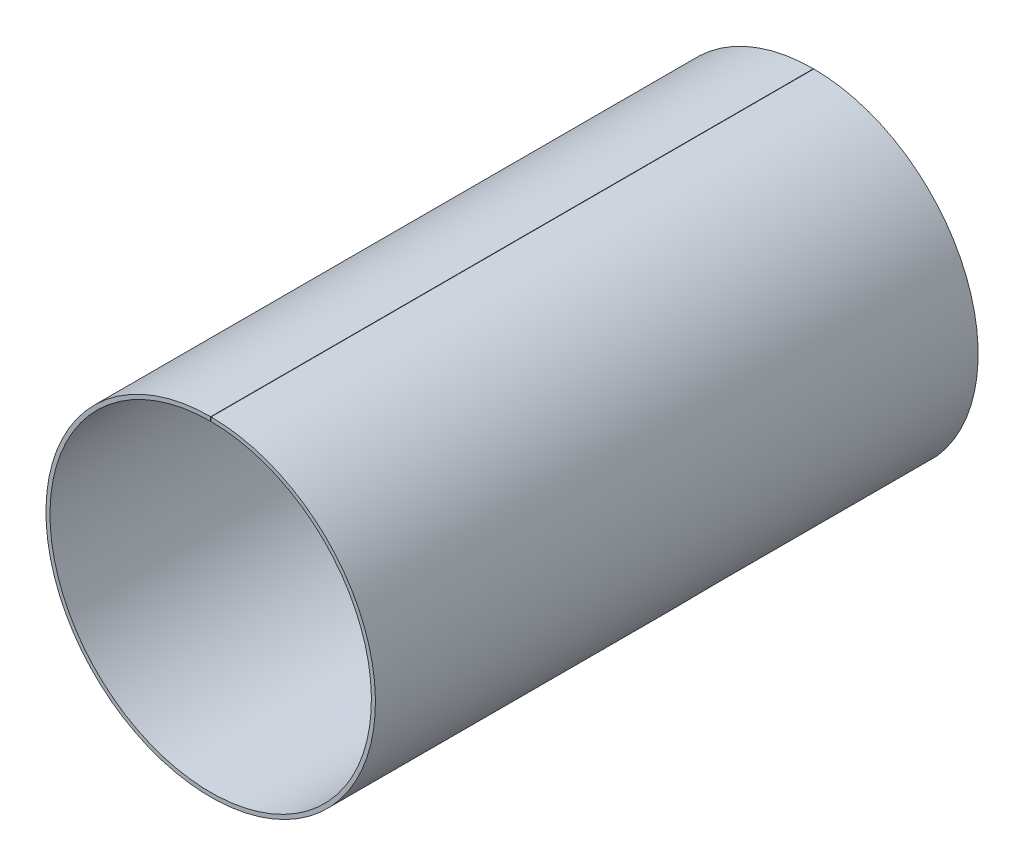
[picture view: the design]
ISO-10303-21;
HEADER;
FILE_DESCRIPTION(('STEP AP214'),'2;1');
FILE_NAME('part.step','',(''),(''),'','','');
FILE_SCHEMA(('AUTOMOTIVE_DESIGN { 1 0 10303 214 1 1 1 1 }'));
ENDSEC;
DATA;
#1=APPLICATION_CONTEXT('core data for automotive mechanical design processes');
#2=APPLICATION_PROTOCOL_DEFINITION('international standard','automotive_design',2000,#1);
#3=PRODUCT_CONTEXT('',#1,'mechanical');
#4=PRODUCT('Part','Part','',(#3));
#5=PRODUCT_RELATED_PRODUCT_CATEGORY('part','',(#4));
#6=PRODUCT_DEFINITION_FORMATION('','',#4);
#7=PRODUCT_DEFINITION_CONTEXT('part definition',#1,'design');
#8=PRODUCT_DEFINITION('design','',#6,#7);
#9=PRODUCT_DEFINITION_SHAPE('','',#8);
#10=(LENGTH_UNIT() NAMED_UNIT(*) SI_UNIT(.MILLI.,.METRE.));
#11=(NAMED_UNIT(*) PLANE_ANGLE_UNIT() SI_UNIT($,.RADIAN.));
#12=(NAMED_UNIT(*) SI_UNIT($,.STERADIAN.) SOLID_ANGLE_UNIT());
#13=UNCERTAINTY_MEASURE_WITH_UNIT(LENGTH_MEASURE(1.E-05),#10,'distance_accuracy_value','');
#14=(GEOMETRIC_REPRESENTATION_CONTEXT(3) GLOBAL_UNCERTAINTY_ASSIGNED_CONTEXT((#13)) GLOBAL_UNIT_ASSIGNED_CONTEXT((#10,
#11,#12)) REPRESENTATION_CONTEXT('',''));
#15=CARTESIAN_POINT('',(0.,0.,0.));
#16=DIRECTION('',(0.,0.,1.));
#17=DIRECTION('',(1.,0.,0.));
#18=AXIS2_PLACEMENT_3D('',#15,#16,#17);
#19=CARTESIAN_POINT('',(39.5,-26.9706118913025,-21.4946060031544));
#20=DIRECTION('',(0.,-1.,0.));
#21=DIRECTION('',(0.,0.,-1.));
#22=AXIS2_PLACEMENT_3D('',#19,#20,#21);
#23=PLANE('',#22);
#24=DIRECTION('',(0.,0.,-1.));
#25=VECTOR('',#24,1.);
#26=CARTESIAN_POINT('',(-29.5395682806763,-26.9706118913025,-21.4946060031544));
#27=LINE('',#26,#25);
#28=CARTESIAN_POINT('',(-29.5395682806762,-26.9706118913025,52.056104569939));
#29=VERTEX_POINT('',#28);
#30=CARTESIAN_POINT('',(-29.5395682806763,-26.9706118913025,0.));
#31=VERTEX_POINT('',#30);
#32=EDGE_CURVE('E13',#29,#31,#27,.T.);
#33=ORIENTED_EDGE('',*,*,#32,.F.);
#34=DIRECTION('',(-1.,0.,0.));
#35=VECTOR('',#34,1.);
#36=CARTESIAN_POINT('',(39.5,-26.9706118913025,52.056104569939));
#37=LINE('',#36,#35);
#38=CARTESIAN_POINT('',(29.5395682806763,-26.9706118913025,52.056104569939));
#39=VERTEX_POINT('',#38);
#40=EDGE_CURVE('E123',#39,#29,#37,.T.);
#41=ORIENTED_EDGE('',*,*,#40,.F.);
#42=DIRECTION('',(0.,0.,1.));
#43=VECTOR('',#42,1.);
#44=CARTESIAN_POINT('',(29.5395682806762,-26.9706118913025,-21.4946060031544));
#45=LINE('',#44,#43);
#46=CARTESIAN_POINT('',(29.5395682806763,-26.9706118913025,0.));
#47=VERTEX_POINT('',#46);
#48=EDGE_CURVE('E127',#47,#39,#45,.T.);
#49=ORIENTED_EDGE('',*,*,#48,.F.);
#50=DIRECTION('',(1.,0.,0.));
#51=VECTOR('',#50,1.);
#52=CARTESIAN_POINT('',(39.5,-26.9706118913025,0.));
#53=LINE('',#52,#51);
#54=EDGE_CURVE('E53',#31,#47,#53,.T.);
#55=ORIENTED_EDGE('',*,*,#54,.F.);
#56=EDGE_LOOP('',(#33,#41,#49,#55));
#57=FACE_BOUND('',#56,.T.);
#58=ADVANCED_FACE('F44',(#57),#23,.F.);
#59=CARTESIAN_POINT('',(39.5,-78.6919749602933,52.056104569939));
#60=DIRECTION('',(-1.,0.,0.));
#61=DIRECTION('',(0.,0.,1.));
#62=AXIS2_PLACEMENT_3D('',#59,#60,#61);
#63=CYLINDRICAL_SURFACE('',#62,51.7213630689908);
#64=CARTESIAN_POINT('',(29.5395682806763,-26.9706118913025,52.056104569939));
#65=CARTESIAN_POINT('',(29.5395838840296,-26.9706015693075,52.5636464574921));
#66=CARTESIAN_POINT('',(29.5328734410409,-26.9780822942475,53.0711946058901));
#67=CARTESIAN_POINT('',(29.5057633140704,-27.0079563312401,54.0856049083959));
#68=CARTESIAN_POINT('',(29.4853603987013,-27.0303531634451,54.5924668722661));
#69=CARTESIAN_POINT('',(29.4306245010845,-27.0899936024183,55.6046296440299));
#70=CARTESIAN_POINT('',(29.3962897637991,-27.1272390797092,56.1099302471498));
#71=CARTESIAN_POINT('',(29.3135458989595,-27.2164300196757,57.1180958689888));
#72=CARTESIAN_POINT('',(29.2651361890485,-27.2683760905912,57.6209607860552));
#73=CARTESIAN_POINT('',(29.1539395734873,-27.3871059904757,58.6263006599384));
#74=CARTESIAN_POINT('',(29.0910718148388,-27.4539731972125,59.1287568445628));
#75=CARTESIAN_POINT('',(28.9505931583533,-27.6020896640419,60.1294458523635));
#76=CARTESIAN_POINT('',(28.8729830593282,-27.6833381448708,60.6276789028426));
#77=CARTESIAN_POINT('',(28.7026729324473,-27.8598685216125,61.6190444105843));
#78=CARTESIAN_POINT('',(28.6099733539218,-27.9551499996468,62.1121770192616));
#79=CARTESIAN_POINT('',(28.4090308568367,-28.1593192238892,63.0924447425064));
#80=CARTESIAN_POINT('',(28.3007870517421,-28.268207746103,63.579579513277));
#81=CARTESIAN_POINT('',(28.0240035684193,-28.5430569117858,64.731149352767));
#82=CARTESIAN_POINT('',(27.8482015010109,-28.714958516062,65.3924441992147));
#83=CARTESIAN_POINT('',(27.46476489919,-29.0821079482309,66.6992258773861));
#84=CARTESIAN_POINT('',(27.2571289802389,-29.2773567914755,67.3447120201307));
#85=CARTESIAN_POINT('',(26.9204212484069,-29.5861166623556,68.2988258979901));
#86=CARTESIAN_POINT('',(26.8039640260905,-29.691695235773,68.6145407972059));
#87=CARTESIAN_POINT('',(26.5624625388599,-29.90785640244,69.2409497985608));
#88=CARTESIAN_POINT('',(26.4374182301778,-30.0184390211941,69.551643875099));
#89=CARTESIAN_POINT('',(26.1789307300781,-30.2439971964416,70.1668732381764));
#90=CARTESIAN_POINT('',(26.0455094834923,-30.3589609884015,70.4714220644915));
#91=CARTESIAN_POINT('',(25.769901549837,-30.5932043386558,71.0748425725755));
#92=CARTESIAN_POINT('',(25.6277148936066,-30.7124838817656,71.3737142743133));
#93=CARTESIAN_POINT('',(25.3343291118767,-30.9549597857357,71.9653736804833));
#94=CARTESIAN_POINT('',(25.1831302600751,-31.0781560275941,72.2581615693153));
#95=CARTESIAN_POINT('',(24.8715628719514,-31.3280545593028,72.8372956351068));
#96=CARTESIAN_POINT('',(24.7111942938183,-31.4547568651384,73.1236417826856));
#97=CARTESIAN_POINT('',(24.3811937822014,-31.7112092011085,73.6894936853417));
#98=CARTESIAN_POINT('',(24.2115630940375,-31.8409588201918,73.9690003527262));
#99=CARTESIAN_POINT('',(23.8629442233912,-32.1030571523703,74.5208645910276));
#100=CARTESIAN_POINT('',(23.6839561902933,-32.2354058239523,74.7932222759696));
#101=CARTESIAN_POINT('',(23.3366679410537,-32.4875528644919,75.3009330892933));
#102=CARTESIAN_POINT('',(23.1693510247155,-32.6071342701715,75.537066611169));
#103=CARTESIAN_POINT('',(22.827179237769,-32.8475787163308,76.0031193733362));
#104=CARTESIAN_POINT('',(22.6523244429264,-32.9684417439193,76.2330386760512));
#105=CARTESIAN_POINT('',(22.1165000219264,-33.3323977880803,76.9131429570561));
#106=CARTESIAN_POINT('',(21.7442121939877,-33.5769002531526,77.3537594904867));
#107=CARTESIAN_POINT('',(20.9694536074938,-34.0662681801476,78.2073537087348));
#108=CARTESIAN_POINT('',(20.566982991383,-34.3111336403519,78.6203315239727));
#109=CARTESIAN_POINT('',(19.7325093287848,-34.7976543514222,79.4167640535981));
#110=CARTESIAN_POINT('',(19.3005239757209,-35.0393114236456,79.8002361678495));
#111=CARTESIAN_POINT('',(18.4079882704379,-35.516223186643,80.5367351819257));
#112=CARTESIAN_POINT('',(17.9474371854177,-35.7514777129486,80.889761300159));
#113=CARTESIAN_POINT('',(16.999006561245,-36.2120302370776,81.5640769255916));
#114=CARTESIAN_POINT('',(16.5111318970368,-36.4373299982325,81.8853720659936));
#115=CARTESIAN_POINT('',(15.6894230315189,-36.7962510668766,82.3860516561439));
#116=CARTESIAN_POINT('',(15.3630761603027,-36.9337801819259,82.5750138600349));
#117=CARTESIAN_POINT('',(14.7003465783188,-37.202549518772,82.9394046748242));
#118=CARTESIAN_POINT('',(14.3639634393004,-37.3337894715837,83.1148327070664));
#119=CARTESIAN_POINT('',(13.6818115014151,-37.5891251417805,83.4519619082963));
#120=CARTESIAN_POINT('',(13.3360440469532,-37.7132218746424,83.6136650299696));
#121=CARTESIAN_POINT('',(12.6357572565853,-37.9535856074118,83.9233517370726));
#122=CARTESIAN_POINT('',(12.2812380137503,-38.0698526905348,84.0713354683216));
#123=CARTESIAN_POINT('',(11.5641165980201,-38.2937981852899,84.3534597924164));
#124=CARTESIAN_POINT('',(11.2015152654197,-38.4014774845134,84.4876018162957));
#125=CARTESIAN_POINT('',(10.4689097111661,-38.6076174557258,84.7420418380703));
#126=CARTESIAN_POINT('',(10.0989054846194,-38.7060781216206,84.862339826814));
#127=CARTESIAN_POINT('',(9.35225008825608,-38.8932301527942,85.0891322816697));
#128=CARTESIAN_POINT('',(8.97559877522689,-38.9819213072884,85.1956264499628));
#129=CARTESIAN_POINT('',(8.2163811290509,-39.1489696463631,85.3947763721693));
#130=CARTESIAN_POINT('',(7.83381487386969,-39.2273269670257,85.4874323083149));
#131=CARTESIAN_POINT('',(7.26854292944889,-39.3344724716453,85.6133565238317));
#132=CARTESIAN_POINT('',(7.08780238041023,-39.3674519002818,85.6519922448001));
#133=CARTESIAN_POINT('',(6.72528306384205,-39.4310094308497,85.7262452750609));
#134=CARTESIAN_POINT('',(6.54350430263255,-39.4615875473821,85.7618626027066));
#135=CARTESIAN_POINT('',(5.99676399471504,-39.5497353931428,85.8642782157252));
#136=CARTESIAN_POINT('',(5.63037673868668,-39.6037227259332,85.9266449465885));
#137=CARTESIAN_POINT('',(4.894462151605,-39.7016651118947,86.0393462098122));
#138=CARTESIAN_POINT('',(4.52493506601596,-39.7456209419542,86.0896816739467));
#139=CARTESIAN_POINT('',(3.78335703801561,-39.8232038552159,86.1782601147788));
#140=CARTESIAN_POINT('',(3.41130612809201,-39.8568310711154,86.2165032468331));
#141=CARTESIAN_POINT('',(2.66540532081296,-39.9135736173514,86.2809030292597));
#142=CARTESIAN_POINT('',(2.2915556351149,-39.9366901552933,86.3070610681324));
#143=CARTESIAN_POINT('',(1.54270343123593,-39.972359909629,86.3473794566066));
#144=CARTESIAN_POINT('',(1.16770089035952,-39.9849129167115,86.361539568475));
#145=CARTESIAN_POINT('',(0.417216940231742,-39.9996005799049,86.3781045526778));
#146=CARTESIAN_POINT('',(0.0417355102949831,-40.0017347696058,86.3805088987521));
#147=CARTESIAN_POINT('',(-0.709024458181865,-39.995461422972,86.373436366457));
#148=CARTESIAN_POINT('',(-1.08430299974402,-39.9870540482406,86.3639596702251));
#149=CARTESIAN_POINT('',(-1.83163941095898,-39.9597840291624,86.3331698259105));
#150=CARTESIAN_POINT('',(-2.20370274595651,-39.9409870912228,86.3119310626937));
#151=CARTESIAN_POINT('',(-2.94630233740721,-39.8930808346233,86.2576618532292));
#152=CARTESIAN_POINT('',(-3.3168385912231,-39.8639714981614,86.2246313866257));
#153=CARTESIAN_POINT('',(-4.05571858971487,-39.7956086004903,86.1467890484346));
#154=CARTESIAN_POINT('',(-4.42406241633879,-39.7563554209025,86.1019776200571));
#155=CARTESIAN_POINT('',(-5.15789471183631,-39.6678283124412,86.0004693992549));
#156=CARTESIAN_POINT('',(-5.52338318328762,-39.6185543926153,85.9437726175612));
#157=CARTESIAN_POINT('',(-6.25084562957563,-39.510284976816,85.8185308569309));
#158=CARTESIAN_POINT('',(-6.61281993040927,-39.4512903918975,85.7499869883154));
#159=CARTESIAN_POINT('',(-7.33261279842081,-39.3238872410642,85.6010391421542));
#160=CARTESIAN_POINT('',(-7.69043137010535,-39.2554786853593,85.5206351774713));
#161=CARTESIAN_POINT('',(-8.75674461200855,-39.0365205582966,85.2614622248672));
#162=CARTESIAN_POINT('',(-9.45824785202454,-38.872215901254,85.0647063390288));
#163=CARTESIAN_POINT('',(-10.4921737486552,-38.6010608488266,84.7338980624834));
#164=CARTESIAN_POINT('',(-10.8337548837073,-38.5065614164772,84.6176853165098));
#165=CARTESIAN_POINT('',(-11.5103387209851,-38.3097601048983,84.3732941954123));
#166=CARTESIAN_POINT('',(-11.84534142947,-38.207458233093,84.245115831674));
#167=CARTESIAN_POINT('',(-12.8395908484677,-37.8896921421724,83.8427383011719));
#168=CARTESIAN_POINT('',(-13.4882439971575,-37.6633237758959,83.5506440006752));
#169=CARTESIAN_POINT('',(-14.7526582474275,-37.1862599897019,82.9192109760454));
#170=CARTESIAN_POINT('',(-15.3684233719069,-36.9355675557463,82.5798780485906));
#171=CARTESIAN_POINT('',(-16.264735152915,-36.5453797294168,82.0363261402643));
#172=CARTESIAN_POINT('',(-16.5589819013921,-36.4129429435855,81.8493600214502));
#173=CARTESIAN_POINT('',(-17.138026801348,-36.1440112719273,81.4640179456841));
#174=CARTESIAN_POINT('',(-17.4228249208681,-36.0075163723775,81.2656419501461));
#175=CARTESIAN_POINT('',(-17.985824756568,-35.7296562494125,80.8554211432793));
#176=CARTESIAN_POINT('',(-18.2639150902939,-35.5882533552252,80.6434491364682));
#177=CARTESIAN_POINT('',(-18.8098334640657,-35.3028267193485,80.208349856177));
#178=CARTESIAN_POINT('',(-19.0776614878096,-35.1588029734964,79.9852225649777));
#179=CARTESIAN_POINT('',(-19.6027570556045,-34.8688616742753,79.5280426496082));
#180=CARTESIAN_POINT('',(-19.8600247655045,-34.7229441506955,79.2939901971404));
#181=CARTESIAN_POINT('',(-20.3637750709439,-34.4299693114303,78.8152725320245));
#182=CARTESIAN_POINT('',(-20.6102576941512,-34.28291199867,78.5706073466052));
#183=CARTESIAN_POINT('',(-21.3333612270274,-33.8411297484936,77.8211389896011));
#184=CARTESIAN_POINT('',(-21.7936904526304,-33.5457651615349,77.3008171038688));
#185=CARTESIAN_POINT('',(-22.6705401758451,-32.9594020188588,76.222366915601));
#186=CARTESIAN_POINT('',(-23.0870585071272,-32.66840367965,75.6642367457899));
#187=CARTESIAN_POINT('',(-23.9019841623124,-32.077492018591,74.4761176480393));
#188=CARTESIAN_POINT('',(-24.2974925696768,-31.7782134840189,73.8438157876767));
#189=CARTESIAN_POINT('',(-24.8545131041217,-31.3418250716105,72.8693153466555));
#190=CARTESIAN_POINT('',(-25.0341634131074,-31.1984359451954,72.5401042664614));
#191=CARTESIAN_POINT('',(-25.3816015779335,-30.9164277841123,71.8734548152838));
#192=CARTESIAN_POINT('',(-25.5493894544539,-30.7778087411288,71.5360164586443));
#193=CARTESIAN_POINT('',(-25.8734672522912,-30.50587456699,70.8532922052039));
#194=CARTESIAN_POINT('',(-26.0297500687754,-30.3725627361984,70.5080016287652));
#195=CARTESIAN_POINT('',(-26.3309193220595,-30.1118558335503,69.8102624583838));
#196=CARTESIAN_POINT('',(-26.4758050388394,-29.9844611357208,69.4578134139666));
#197=CARTESIAN_POINT('',(-26.7544398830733,-29.7360957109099,68.7463191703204));
#198=CARTESIAN_POINT('',(-26.8881891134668,-29.6151249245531,68.3872740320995));
#199=CARTESIAN_POINT('',(-27.144841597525,-29.3800522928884,67.66310970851));
#200=CARTESIAN_POINT('',(-27.2677447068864,-29.2659505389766,67.2979904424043));
#201=CARTESIAN_POINT('',(-27.518309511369,-29.0306007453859,66.5141771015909));
#202=CARTESIAN_POINT('',(-27.6444999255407,-28.9103626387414,66.0947083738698));
#203=CARTESIAN_POINT('',(-27.8837417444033,-28.6796954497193,65.2494074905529));
#204=CARTESIAN_POINT('',(-27.9967937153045,-28.5692659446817,64.8235756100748));
#205=CARTESIAN_POINT('',(-28.2102645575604,-28.3586374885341,63.9661600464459));
#206=CARTESIAN_POINT('',(-28.3106811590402,-28.2584403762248,63.5345753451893));
#207=CARTESIAN_POINT('',(-28.4990025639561,-28.0686764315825,62.6664108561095));
#208=CARTESIAN_POINT('',(-28.5869075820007,-27.9791094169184,62.2298311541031));
#209=CARTESIAN_POINT('',(-28.832220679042,-27.7269373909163,60.9139284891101));
#210=CARTESIAN_POINT('',(-28.9713653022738,-27.5807231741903,60.0278813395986));
#211=CARTESIAN_POINT('',(-29.1457292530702,-27.3958393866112,58.6900280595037));
#212=CARTESIAN_POINT('',(-29.198123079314,-27.3399532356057,58.2426387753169));
#213=CARTESIAN_POINT('',(-29.2915837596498,-27.2397978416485,57.3453836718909));
#214=CARTESIAN_POINT('',(-29.33265155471,-27.1955276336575,56.8955180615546));
#215=CARTESIAN_POINT('',(-29.3968605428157,-27.126097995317,56.0802329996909));
#216=CARTESIAN_POINT('',(-29.4219284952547,-27.0989024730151,55.7151342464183));
#217=CARTESIAN_POINT('',(-29.4648432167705,-27.0522577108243,54.9840859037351));
#218=CARTESIAN_POINT('',(-29.4826912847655,-27.0328070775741,54.618136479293));
#219=CARTESIAN_POINT('',(-29.5254092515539,-26.9861753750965,53.5208220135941));
#220=CARTESIAN_POINT('',(-29.5395682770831,-26.970589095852,52.7885185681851));
#221=CARTESIAN_POINT('',(-29.5395682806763,-26.9706118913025,52.0561045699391));
#222=B_SPLINE_CURVE_WITH_KNOTS('',3,(#64,#65,#66,#67,#68,#69,#70,#71,#72,#73,#74,#75,#76,#77,
#78,#79,#80,#81,#82,#83,#84,#85,#86,#87,#88,#89,#90,#91,#92,#93,#94,#95,#96,#97,#98,#99,#100,
#101,#102,#103,#104,#105,#106,#107,#108,#109,#110,#111,#112,#113,#114,#115,#116,#117,#118,#119,
#120,#121,#122,#123,#124,#125,#126,#127,#128,#129,#130,#131,#132,#133,#134,#135,#136,#137,#138,
#139,#140,#141,#142,#143,#144,#145,#146,#147,#148,#149,#150,#151,#152,#153,#154,#155,#156,#157,
#158,#159,#160,#161,#162,#163,#164,#165,#166,#167,#168,#169,#170,#171,#172,#173,#174,#175,#176,
#177,#178,#179,#180,#181,#182,#183,#184,#185,#186,#187,#188,#189,#190,#191,#192,#193,#194,#195,
#196,#197,#198,#199,#200,#201,#202,#203,#204,#205,#206,#207,#208,#209,#210,#211,#212,#213,#214,
#215,#216,#217,#218,#219,#220,#221),.UNSPECIFIED.,.F.,.F.,(4,2,2,2,2,2,2,2,2,2,2,2,2,2,2,2,2,2,
2,2,2,2,2,2,2,2,2,2,2,2,2,2,2,2,2,2,2,2,2,2,2,2,2,2,2,2,2,2,2,2,2,2,2,2,2,2,2,2,2,2,2,2,2,2,2,2,
2,2,2,2,2,2,2,2,2,2,2,2,4),(0.,1.52253485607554,3.04542915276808,4.56851535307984,
6.09166458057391,7.62354818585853,9.15534880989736,10.6871038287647,12.2189462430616,
14.3342520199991,16.4496498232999,17.5075509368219,18.5654574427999,19.6206997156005,
20.675938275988,21.7311448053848,22.7863561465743,23.8414259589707,24.8964789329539,
25.8357263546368,26.7749643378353,28.6531062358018,30.5312392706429,32.4082561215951,
34.2853211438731,36.1620523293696,37.3658978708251,38.5697948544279,39.773520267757,
40.9772328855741,42.1808209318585,43.3844097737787,44.5880245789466,45.7916235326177,
46.3548176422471,46.9180083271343,48.0443219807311,49.1705483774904,50.2967603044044,
51.4228428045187,52.5489476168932,53.6751028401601,54.8012407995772,55.9203369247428,
57.0394349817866,58.1584909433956,59.2775458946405,60.3964960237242,61.5154449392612,
63.7528794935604,64.8715563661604,65.9902321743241,68.2270492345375,70.4635920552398,
71.5821197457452,72.7006512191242,73.831863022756,74.9630766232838,76.0942724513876,
77.2254653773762,79.4876245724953,81.7498955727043,84.158018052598,85.3623349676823,
86.5666497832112,87.7717021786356,88.9768306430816,90.1819479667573,91.3870813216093,
92.7494495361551,94.1117590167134,95.4743128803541,96.8368433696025,99.5601272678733,
100.92161511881,102.282989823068,103.383745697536,104.48430344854,106.680979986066),.UNSPECIFIED.);
#223=EDGE_CURVE('E118',#39,#29,#222,.T.);
#224=ORIENTED_EDGE('',*,*,#223,.F.);
#225=ORIENTED_EDGE('',*,*,#40,.T.);
#226=EDGE_LOOP('',(#224,#225));
#227=FACE_BOUND('',#226,.T.);
#228=ADVANCED_FACE('F46',(#227),#63,.T.);
#229=CARTESIAN_POINT('',(-29.5395682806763,-79.,52.0561045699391));
#230=CARTESIAN_POINT('',(-29.5395682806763,-79.,53.1763672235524));
#231=CARTESIAN_POINT('',(-29.5064943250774,-79.,54.2934366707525));
#232=CARTESIAN_POINT('',(-29.3734448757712,-79.,56.5211935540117));
#233=CARTESIAN_POINT('',(-29.2730099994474,-79.,57.6341666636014));
#234=CARTESIAN_POINT('',(-28.8704443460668,-79.,60.9235356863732));
#235=CARTESIAN_POINT('',(-28.4687298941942,-79.,63.062514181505));
#236=CARTESIAN_POINT('',(-27.7696087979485,-79.,65.6657140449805));
#237=CARTESIAN_POINT('',(-27.6197912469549,-79.,66.1827959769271));
#238=CARTESIAN_POINT('',(-27.2987920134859,-79.,67.2096347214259));
#239=CARTESIAN_POINT('',(-27.1273256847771,-79.,67.7200196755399));
#240=CARTESIAN_POINT('',(-26.5838758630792,-79.,69.2255062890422));
#241=CARTESIAN_POINT('',(-26.1816428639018,-79.,70.1995239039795));
#242=CARTESIAN_POINT('',(-25.2895618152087,-79.,72.0876914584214));
#243=CARTESIAN_POINT('',(-24.7997306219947,-79.,73.0018414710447));
#244=CARTESIAN_POINT('',(-23.9911705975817,-79.,74.3267571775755));
#245=CARTESIAN_POINT('',(-23.7093229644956,-79.,74.7606675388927));
#246=CARTESIAN_POINT('',(-23.1192699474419,-79.,75.6126684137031));
#247=CARTESIAN_POINT('',(-22.8119320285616,-79.,76.0293579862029));
#248=CARTESIAN_POINT('',(-21.2236269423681,-79.,78.0506325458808));
#249=CARTESIAN_POINT('',(-19.7784331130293,-79.,79.4855025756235));
#250=CARTESIAN_POINT('',(-17.7196545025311,-79.,81.0562316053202));
#251=CARTESIAN_POINT('',(-17.2937490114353,-79.,81.3600587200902));
#252=CARTESIAN_POINT('',(-16.4253678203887,-79.,81.9385987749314));
#253=CARTESIAN_POINT('',(-15.9824372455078,-79.,82.213810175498));
#254=CARTESIAN_POINT('',(-14.6274490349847,-79.,82.9988478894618));
#255=CARTESIAN_POINT('',(-13.689258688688,-79.,83.4682011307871));
#256=CARTESIAN_POINT('',(-11.7418961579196,-79.,84.3044274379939));
#257=CARTESIAN_POINT('',(-10.7317960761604,-79.,84.6716161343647));
#258=CARTESIAN_POINT('',(-8.6409206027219,-79.,85.3036230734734));
#259=CARTESIAN_POINT('',(-7.58068307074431,-79.,85.5624142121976));
#260=CARTESIAN_POINT('',(-5.43163462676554,-79.,85.9746089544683));
#261=CARTESIAN_POINT('',(-4.34282549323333,-79.,86.1280051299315));
#262=CARTESIAN_POINT('',(-2.68800739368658,-79.,86.2807664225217));
#263=CARTESIAN_POINT('',(-2.13279069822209,-79.,86.3187465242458));
#264=CARTESIAN_POINT('',(-1.01497661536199,-79.,86.3684573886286));
#265=CARTESIAN_POINT('',(-0.452541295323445,-79.,86.3800563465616));
#266=CARTESIAN_POINT('',(2.3379458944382,-79.,86.3717549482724));
#267=CARTESIAN_POINT('',(4.53386139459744,-79.,86.1592950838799));
#268=CARTESIAN_POINT('',(7.23317552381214,-79.,85.6252385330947));
#269=CARTESIAN_POINT('',(7.77266018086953,-79.,85.5042156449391));
#270=CARTESIAN_POINT('',(8.83641887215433,-79.,85.2360927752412));
#271=CARTESIAN_POINT('',(9.35997291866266,-79.,85.0893040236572));
#272=CARTESIAN_POINT('',(10.9063212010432,-79.,84.6107707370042));
#273=CARTESIAN_POINT('',(11.9048684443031,-79.,84.2410025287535));
#274=CARTESIAN_POINT('',(13.838890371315,-79.,83.3962387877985));
#275=CARTESIAN_POINT('',(14.7743490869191,-79.,82.9212316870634));
#276=CARTESIAN_POINT('',(16.1299483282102,-79.,82.123605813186));
#277=CARTESIAN_POINT('',(16.5752666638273,-79.,81.8424608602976));
#278=CARTESIAN_POINT('',(17.4375009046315,-79.,81.2590329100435));
#279=CARTESIAN_POINT('',(17.8556482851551,-79.,80.9561541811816));
#280=CARTESIAN_POINT('',(19.8845351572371,-79.,79.3863446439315));
#281=CARTESIAN_POINT('',(21.3110782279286,-79.,77.9542588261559));
#282=CARTESIAN_POINT('',(22.880321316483,-79.,75.9380460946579));
#283=CARTESIAN_POINT('',(23.1833954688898,-79.,75.5234328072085));
#284=CARTESIAN_POINT('',(23.7685071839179,-79.,74.6710625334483));
#285=CARTESIAN_POINT('',(24.0504682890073,-79.,74.2331706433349));
#286=CARTESIAN_POINT('',(24.8547252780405,-79.,72.9032727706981));
#287=CARTESIAN_POINT('',(25.3398075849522,-79.,71.9891009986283));
#288=CARTESIAN_POINT('',(26.6611382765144,-79.,69.167872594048));
#289=CARTESIAN_POINT('',(27.3649038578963,-79.,67.1826882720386));
#290=CARTESIAN_POINT('',(28.061839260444,-79.,64.5749259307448));
#291=CARTESIAN_POINT('',(28.1922774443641,-79.,64.0455832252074));
#292=CARTESIAN_POINT('',(28.4333484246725,-79.,62.9822659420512));
#293=CARTESIAN_POINT('',(28.5440046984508,-79.,62.4485186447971));
#294=CARTESIAN_POINT('',(28.8481159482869,-79.,60.8411963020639));
#295=CARTESIAN_POINT('',(29.0138322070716,-79.,59.7615563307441));
#296=CARTESIAN_POINT('',(29.4094503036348,-79.,56.4992499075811));
#297=CARTESIAN_POINT('',(29.5395682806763,-79.,54.2934460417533));
#298=CARTESIAN_POINT('',(29.5395682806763,-79.,52.056104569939));
#299=B_SPLINE_CURVE_WITH_KNOTS('',3,(#229,#230,#231,#232,#233,#234,#235,#236,#237,#238,#239,
#240,#241,#242,#243,#244,#245,#246,#247,#248,#249,#250,#251,#252,#253,#254,#255,#256,#257,#258,
#259,#260,#261,#262,#263,#264,#265,#266,#267,#268,#269,#270,#271,#272,#273,#274,#275,#276,#277,
#278,#279,#280,#281,#282,#283,#284,#285,#286,#287,#288,#289,#290,#291,#292,#293,#294,#295,#296,
#297,#298),.UNSPECIFIED.,.F.,.F.,(4,2,2,2,2,2,2,2,2,2,2,2,2,2,2,2,2,2,2,2,2,2,2,2,2,2,2,2,2,2,2,
2,2,2,4),(0.,0.0312500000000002,0.0625000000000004,0.125000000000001,0.140625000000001,
0.156250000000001,0.187500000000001,0.218750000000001,0.234375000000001,0.250000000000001,
0.312500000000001,0.328125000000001,0.343750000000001,0.375000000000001,0.406250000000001,
0.4375,0.46875,0.484375,0.5,0.5625,0.578125,0.59375,0.625,0.65625,0.671875,0.6875,0.75,0.765625,
0.781249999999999,0.812499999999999,0.874999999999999,0.890624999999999,0.906249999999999,
0.937499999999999,1.),.UNSPECIFIED.);
#300=DIRECTION('',(0.,1.,0.));
#301=VECTOR('',#300,1.);
#302=SURFACE_OF_LINEAR_EXTRUSION('',#299,#301);
#303=ORIENTED_EDGE('',*,*,#223,.T.);
#304=DIRECTION('',(0.,1.,0.));
#305=VECTOR('',#304,1.);
#306=CARTESIAN_POINT('',(-29.5395682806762,-79.,52.056104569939));
#307=LINE('',#306,#305);
#308=CARTESIAN_POINT('',(-29.5395682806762,-27.9706118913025,52.056104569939));
#309=VERTEX_POINT('',#308);
#310=EDGE_CURVE('E89',#309,#29,#307,.T.);
#311=ORIENTED_EDGE('',*,*,#310,.F.);
#312=CARTESIAN_POINT('',(29.5395682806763,-27.9706118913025,52.056104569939));
#313=CARTESIAN_POINT('',(29.5395842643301,-27.9706012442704,52.5640136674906));
#314=CARTESIAN_POINT('',(29.5328637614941,-27.9782405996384,53.0719289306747));
#315=CARTESIAN_POINT('',(29.5057147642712,-28.0087474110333,54.0870492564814));
#316=CARTESIAN_POINT('',(29.4852831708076,-28.0316183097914,54.5942541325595));
#317=CARTESIAN_POINT('',(29.4304734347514,-28.092519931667,55.6070620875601));
#318=CARTESIAN_POINT('',(29.3960936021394,-28.1305524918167,56.1126649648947));
#319=CARTESIAN_POINT('',(29.3132480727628,-28.2216260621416,57.1213784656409));
#320=CARTESIAN_POINT('',(29.2647818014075,-28.2746676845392,57.6244889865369));
#321=CARTESIAN_POINT('',(29.1535047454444,-28.395856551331,58.6299019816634));
#322=CARTESIAN_POINT('',(29.0906228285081,-28.4640786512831,59.1321875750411));
#323=CARTESIAN_POINT('',(28.9501384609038,-28.6151826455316,60.1324512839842));
#324=CARTESIAN_POINT('',(28.8725368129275,-28.6980637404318,60.6304296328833));
#325=CARTESIAN_POINT('',(28.7022779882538,-28.8781284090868,61.6211889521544));
#326=CARTESIAN_POINT('',(28.609621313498,-28.9753115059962,62.1139700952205));
#327=CARTESIAN_POINT('',(28.4088148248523,-29.1835412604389,63.093422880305));
#328=CARTESIAN_POINT('',(28.3006642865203,-29.2945885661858,63.5800942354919));
#329=CARTESIAN_POINT('',(28.0257337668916,-29.573295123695,64.7239453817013));
#330=CARTESIAN_POINT('',(27.8520128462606,-29.746762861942,65.3780682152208));
#331=CARTESIAN_POINT('',(27.4735662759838,-30.1170204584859,66.670565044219));
#332=CARTESIAN_POINT('',(27.2688394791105,-30.3138111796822,67.3089384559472));
#333=CARTESIAN_POINT('',(26.8265439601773,-30.7286866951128,68.5672645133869));
#334=CARTESIAN_POINT('',(26.5889732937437,-30.9467727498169,69.1872160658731));
#335=CARTESIAN_POINT('',(26.2074972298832,-31.2877198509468,70.1004582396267));
#336=CARTESIAN_POINT('',(26.0763081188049,-31.4035384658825,70.4017728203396));
#337=CARTESIAN_POINT('',(25.8054125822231,-31.6395286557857,70.998832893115));
#338=CARTESIAN_POINT('',(25.6657061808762,-31.7597002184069,71.2945784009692));
#339=CARTESIAN_POINT('',(25.3775537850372,-32.0040067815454,71.8801038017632));
#340=CARTESIAN_POINT('',(25.2291079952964,-32.128141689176,72.1698838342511));
#341=CARTESIAN_POINT('',(24.9233177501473,-32.3799745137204,72.743136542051));
#342=CARTESIAN_POINT('',(24.7659732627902,-32.5076724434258,73.0266091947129));
#343=CARTESIAN_POINT('',(24.4423003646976,-32.7661894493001,73.5868748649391));
#344=CARTESIAN_POINT('',(24.2759730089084,-32.8970081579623,73.8636686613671));
#345=CARTESIAN_POINT('',(23.9342376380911,-33.1613288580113,74.4102785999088));
#346=CARTESIAN_POINT('',(23.7588297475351,-33.2948308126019,74.6800948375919));
#347=CARTESIAN_POINT('',(23.4170606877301,-33.5503998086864,75.1854519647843));
#348=CARTESIAN_POINT('',(23.2515823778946,-33.672255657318,75.4216967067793));
#349=CARTESIAN_POINT('',(22.9131695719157,-33.9173640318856,75.888022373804));
#350=CARTESIAN_POINT('',(22.7402351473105,-34.0406165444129,76.1181033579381));
#351=CARTESIAN_POINT('',(22.2102883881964,-34.4119175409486,76.7987829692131));
#352=CARTESIAN_POINT('',(21.8420769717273,-34.6615513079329,77.2399006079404));
#353=CARTESIAN_POINT('',(21.0757905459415,-35.1616683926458,78.0948153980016));
#354=CARTESIAN_POINT('',(20.6777156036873,-35.4121517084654,78.5086126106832));
#355=CARTESIAN_POINT('',(19.8521634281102,-35.9104344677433,79.3071192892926));
#356=CARTESIAN_POINT('',(19.4247010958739,-36.158235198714,79.6918432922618));
#357=CARTESIAN_POINT('',(18.76219479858,-36.5254120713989,80.2462953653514));
#358=CARTESIAN_POINT('',(18.5377872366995,-36.6470604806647,80.4273548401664));
#359=CARTESIAN_POINT('',(18.0820007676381,-36.8884434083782,80.7818313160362));
#360=CARTESIAN_POINT('',(17.8506219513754,-37.0081779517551,80.9552484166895));
#361=CARTESIAN_POINT('',(17.3810604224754,-37.2452478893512,81.2942349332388));
#362=CARTESIAN_POINT('',(17.1428788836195,-37.3625836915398,81.4598056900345));
#363=CARTESIAN_POINT('',(16.6598488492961,-37.5944458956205,81.7830172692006));
#364=CARTESIAN_POINT('',(16.4150000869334,-37.7089721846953,81.9406577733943));
#365=CARTESIAN_POINT('',(15.8456336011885,-37.9681576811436,82.2933062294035));
#366=CARTESIAN_POINT('',(15.5189368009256,-38.1117306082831,82.4856057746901));
#367=CARTESIAN_POINT('',(14.8552240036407,-38.3925580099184,82.8565557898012));
#368=CARTESIAN_POINT('',(14.5182075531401,-38.5298122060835,83.0352056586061));
#369=CARTESIAN_POINT('',(13.83446436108,-38.7971026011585,83.3786713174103));
#370=CARTESIAN_POINT('',(13.487738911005,-38.927139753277,83.5434889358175));
#371=CARTESIAN_POINT('',(12.7852033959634,-39.1792400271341,83.8592689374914));
#372=CARTESIAN_POINT('',(12.4293934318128,-39.3013032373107,84.0102314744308));
#373=CARTESIAN_POINT('',(11.7093936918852,-39.5366364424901,84.2981688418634));
#374=CARTESIAN_POINT('',(11.3452055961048,-39.6499081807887,84.4351464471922));
#375=CARTESIAN_POINT('',(10.6090779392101,-39.8669569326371,84.6950893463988));
#376=CARTESIAN_POINT('',(10.2371383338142,-39.9707338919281,84.8180545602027));
#377=CARTESIAN_POINT('',(9.48628554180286,-40.1681890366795,85.05000976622));
#378=CARTESIAN_POINT('',(9.10737228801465,-40.2618671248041,85.1589996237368));
#379=CARTESIAN_POINT('',(8.3433070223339,-40.4384885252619,85.3629456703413));
#380=CARTESIAN_POINT('',(7.95815511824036,-40.5214320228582,85.4579021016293));
#381=CARTESIAN_POINT('',(7.39049950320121,-40.6346454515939,85.5866768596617));
#382=CARTESIAN_POINT('',(7.21008829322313,-40.6693088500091,85.6259731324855));
#383=CARTESIAN_POINT('',(6.84818051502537,-40.7361689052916,85.7015501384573));
#384=CARTESIAN_POINT('',(6.66668394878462,-40.7683655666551,85.7378308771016));
#385=CARTESIAN_POINT('',(6.12072574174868,-40.8612692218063,85.8422417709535));
#386=CARTESIAN_POINT('',(5.75477284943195,-40.9182944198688,85.9059457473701));
#387=CARTESIAN_POINT('',(5.0195687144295,-41.0220366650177,86.0213580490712));
#388=CARTESIAN_POINT('',(4.65031774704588,-41.068754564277,86.0730673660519));
#389=CARTESIAN_POINT('',(3.90913909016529,-41.151533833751,86.1643990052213));
#390=CARTESIAN_POINT('',(3.53721144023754,-41.1875953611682,86.2040215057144));
#391=CARTESIAN_POINT('',(2.79143591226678,-41.2488422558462,86.2711680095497));
#392=CARTESIAN_POINT('',(2.41758839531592,-41.2740295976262,86.2986942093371));
#393=CARTESIAN_POINT('',(1.66864736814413,-41.3134535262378,86.341722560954));
#394=CARTESIAN_POINT('',(1.29355383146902,-41.3276898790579,86.3572244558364));
#395=CARTESIAN_POINT('',(0.167447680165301,-41.3541504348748,86.3860425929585));
#396=CARTESIAN_POINT('',(-0.584541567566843,-41.350138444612,86.3816846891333));
#397=CARTESIAN_POINT('',(-2.06997966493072,-41.2987743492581,86.3257204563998));
#398=CARTESIAN_POINT('',(-2.80349530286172,-41.2523025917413,86.2750738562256));
#399=CARTESIAN_POINT('',(-3.8972926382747,-41.1518979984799,86.1647776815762));
#400=CARTESIAN_POINT('',(-4.26084358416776,-41.1133089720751,86.1222860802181));
#401=CARTESIAN_POINT('',(-4.98521432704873,-41.0260378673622,86.0257694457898));
#402=CARTESIAN_POINT('',(-5.34603412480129,-40.97735579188,85.9717444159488));
#403=CARTESIAN_POINT('',(-6.06426630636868,-40.8701777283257,85.8521807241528));
#404=CARTESIAN_POINT('',(-6.42167893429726,-40.8116824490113,85.7866428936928));
#405=CARTESIAN_POINT('',(-7.13248594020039,-40.6852279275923,85.6440920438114));
#406=CARTESIAN_POINT('',(-7.48588032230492,-40.6172686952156,85.5670790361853));
#407=CARTESIAN_POINT('',(-8.53914756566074,-40.3995599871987,85.3186417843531));
#408=CARTESIAN_POINT('',(-9.2322468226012,-40.235958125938,85.1297957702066));
#409=CARTESIAN_POINT('',(-10.2548308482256,-39.9655429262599,84.8118582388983));
#410=CARTESIAN_POINT('',(-10.5931606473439,-39.8711343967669,84.6999784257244));
#411=CARTESIAN_POINT('',(-11.2634680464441,-39.674432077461,84.4646153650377));
#412=CARTESIAN_POINT('',(-11.5954456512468,-39.5721382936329,84.3411321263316));
#413=CARTESIAN_POINT('',(-12.2524778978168,-39.3602157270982,84.0826139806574));
#414=CARTESIAN_POINT('',(-12.577532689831,-39.2505871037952,83.9475793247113));
#415=CARTESIAN_POINT('',(-13.2202200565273,-39.0245982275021,83.6660475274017));
#416=CARTESIAN_POINT('',(-13.5378526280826,-38.9082379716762,83.5195503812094));
#417=CARTESIAN_POINT('',(-14.4788509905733,-38.5498952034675,83.062874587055));
#418=CARTESIAN_POINT('',(-15.0905002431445,-38.2985912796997,82.7354398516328));
#419=CARTESIAN_POINT('',(-15.9815626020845,-37.9071897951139,82.2107989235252));
#420=CARTESIAN_POINT('',(-16.2742136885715,-37.7742988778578,82.0303144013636));
#421=CARTESIAN_POINT('',(-16.8504088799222,-37.5043385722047,81.6582688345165));
#422=CARTESIAN_POINT('',(-17.133952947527,-37.3672691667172,81.4667077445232));
#423=CARTESIAN_POINT('',(-17.9840074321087,-36.9441481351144,80.8661554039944));
#424=CARTESIAN_POINT('',(-18.5356328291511,-36.6525142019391,80.439699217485));
#425=CARTESIAN_POINT('',(-19.3316521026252,-36.2088893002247,79.7674081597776));
#426=CARTESIAN_POINT('',(-19.5917797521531,-36.0599701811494,79.5378521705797));
#427=CARTESIAN_POINT('',(-20.1014154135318,-35.760760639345,79.0680467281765));
#428=CARTESIAN_POINT('',(-20.3509234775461,-35.6104702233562,78.8277973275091));
#429=CARTESIAN_POINT('',(-20.8391625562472,-35.3092839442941,78.3369286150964));
#430=CARTESIAN_POINT('',(-21.0778929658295,-35.1583880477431,78.0863087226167));
#431=CARTESIAN_POINT('',(-21.5445034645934,-34.8567437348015,77.5750643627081));
#432=CARTESIAN_POINT('',(-21.7723827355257,-34.7059953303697,77.3144391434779));
#433=CARTESIAN_POINT('',(-22.4397462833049,-34.2551203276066,76.5182060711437));
#434=CARTESIAN_POINT('',(-22.8630437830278,-33.956309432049,75.9681525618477));
#435=CARTESIAN_POINT('',(-23.6935509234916,-33.3477047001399,74.7941767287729));
#436=CARTESIAN_POINT('',(-24.0977174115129,-33.0385424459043,74.1677746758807));
#437=CARTESIAN_POINT('',(-24.6676374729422,-32.5870333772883,73.2012641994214));
#438=CARTESIAN_POINT('',(-24.8515738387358,-32.4385539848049,72.8745726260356));
#439=CARTESIAN_POINT('',(-25.2075152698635,-32.146303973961,72.2126925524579));
#440=CARTESIAN_POINT('',(-25.3795203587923,-32.002533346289,71.8775040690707));
#441=CARTESIAN_POINT('',(-25.8781983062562,-31.5790927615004,70.859638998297));
#442=CARTESIAN_POINT('',(-26.1873683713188,-31.3074266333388,70.1649450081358));
#443=CARTESIAN_POINT('',(-26.7607244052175,-30.7899134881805,68.7479635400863));
#444=CARTESIAN_POINT('',(-27.0249086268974,-30.5440674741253,68.0256749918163));
#445=CARTESIAN_POINT('',(-27.4038205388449,-30.1833792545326,66.8803799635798));
#446=CARTESIAN_POINT('',(-27.533215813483,-30.0584369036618,66.4653105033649));
#447=CARTESIAN_POINT('',(-27.7789002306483,-29.8182987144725,65.6284969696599));
#448=CARTESIAN_POINT('',(-27.8951890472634,-29.7031031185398,65.2067527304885));
#449=CARTESIAN_POINT('',(-28.1151975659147,-29.4829349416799,64.3573088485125));
#450=CARTESIAN_POINT('',(-28.2189157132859,-29.377963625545,63.9296084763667));
#451=CARTESIAN_POINT('',(-28.4139291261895,-29.1786486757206,63.0689290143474));
#452=CARTESIAN_POINT('',(-28.5052243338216,-29.0843050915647,62.6359498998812));
#453=CARTESIAN_POINT('',(-28.6756146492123,-28.9066299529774,61.7655490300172));
#454=CARTESIAN_POINT('',(-28.7547146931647,-28.823293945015,61.3281291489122));
#455=CARTESIAN_POINT('',(-28.9010694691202,-28.6678828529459,60.4493160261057));
#456=CARTESIAN_POINT('',(-28.9683238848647,-28.5958080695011,60.0079226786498));
#457=CARTESIAN_POINT('',(-29.0914131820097,-28.4631904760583,59.1219699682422));
#458=CARTESIAN_POINT('',(-29.1472516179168,-28.4026440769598,58.6774116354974));
#459=CARTESIAN_POINT('',(-29.2476512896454,-28.293250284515,57.785593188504));
#460=CARTESIAN_POINT('',(-29.2922126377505,-28.2444027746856,57.3383331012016));
#461=CARTESIAN_POINT('',(-29.3661484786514,-28.1630847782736,56.488966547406));
#462=CARTESIAN_POINT('',(-29.3966285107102,-28.1294309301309,56.0870685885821));
#463=CARTESIAN_POINT('',(-29.4487881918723,-28.0716974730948,55.2820900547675));
#464=CARTESIAN_POINT('',(-29.4704694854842,-28.0476160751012,54.8790097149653));
#465=CARTESIAN_POINT('',(-29.5050813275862,-28.0091191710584,54.0728536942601));
#466=CARTESIAN_POINT('',(-29.5180299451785,-27.9946837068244,53.6697797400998));
#467=CARTESIAN_POINT('',(-29.5352792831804,-27.9754274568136,52.8631720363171));
#468=CARTESIAN_POINT('',(-29.5395790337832,-27.9706077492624,52.4596382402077));
#469=CARTESIAN_POINT('',(-29.5395682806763,-27.9706118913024,52.0561045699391));
#470=B_SPLINE_CURVE_WITH_KNOTS('',3,(#312,#313,#314,#315,#316,#317,#318,#319,#320,#321,#322,
#323,#324,#325,#326,#327,#328,#329,#330,#331,#332,#333,#334,#335,#336,#337,#338,#339,#340,#341,
#342,#343,#344,#345,#346,#347,#348,#349,#350,#351,#352,#353,#354,#355,#356,#357,#358,#359,#360,
#361,#362,#363,#364,#365,#366,#367,#368,#369,#370,#371,#372,#373,#374,#375,#376,#377,#378,#379,
#380,#381,#382,#383,#384,#385,#386,#387,#388,#389,#390,#391,#392,#393,#394,#395,#396,#397,#398,
#399,#400,#401,#402,#403,#404,#405,#406,#407,#408,#409,#410,#411,#412,#413,#414,#415,#416,#417,
#418,#419,#420,#421,#422,#423,#424,#425,#426,#427,#428,#429,#430,#431,#432,#433,#434,#435,#436,
#437,#438,#439,#440,#441,#442,#443,#444,#445,#446,#447,#448,#449,#450,#451,#452,#453,#454,#455,
#456,#457,#458,#459,#460,#461,#462,#463,#464,#465,#466,#467,#468,#469),.UNSPECIFIED.,.F.,.F.,(4,
2,2,2,2,2,2,2,2,2,2,2,2,2,2,2,2,2,2,2,2,2,2,2,2,2,2,2,2,2,2,2,2,2,2,2,2,2,2,2,2,2,2,2,2,2,2,2,2,
2,2,2,2,2,2,2,2,2,2,2,2,2,2,2,2,2,2,2,2,2,2,2,2,2,2,2,2,2,4),(0.,1.5236339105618,
3.04761231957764,4.57177543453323,6.09600072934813,7.62791550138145,9.15974675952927,
10.6915269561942,12.223378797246,14.3181108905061,16.4129205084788,18.5078541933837,
19.5530503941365,20.5982436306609,21.6434123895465,22.6885849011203,23.733634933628,
24.778670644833,25.7178714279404,26.6570632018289,28.5351238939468,30.4131803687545,
32.2902914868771,33.2290067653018,34.1677098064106,35.1062518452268,36.0448315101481,
37.260513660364,38.4762493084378,39.6918240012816,40.9073852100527,42.1227047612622,
43.3380312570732,44.5533694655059,45.7686866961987,46.332251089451,46.8958144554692,
48.0228699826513,49.1498322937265,50.2767779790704,51.4035189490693,52.5302839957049,
54.7833590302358,56.9907541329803,58.0946428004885,59.1985311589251,60.302339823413,
61.4061473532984,63.6133263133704,64.7190140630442,65.8247009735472,66.9303638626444,
68.0360272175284,70.2467402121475,71.3523516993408,72.4579677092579,74.7223267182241,
75.8547319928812,76.9871317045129,78.1195949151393,79.2521433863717,81.516834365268,
83.935273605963,85.1447552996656,86.3542346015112,88.7742493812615,91.194358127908,
92.5511605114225,93.9079966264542,95.265000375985,96.6220104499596,97.9784698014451,
99.3349653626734,100.691037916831,102.047096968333,103.260254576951,104.473185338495,
105.683598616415,106.894147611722),.UNSPECIFIED.);
#471=CARTESIAN_POINT('',(29.5395682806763,-27.9706118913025,52.056104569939));
#472=VERTEX_POINT('',#471);
#473=EDGE_CURVE('E103',#472,#309,#470,.T.);
#474=ORIENTED_EDGE('',*,*,#473,.F.);
#475=DIRECTION('',(0.,1.,0.));
#476=VECTOR('',#475,1.);
#477=CARTESIAN_POINT('',(29.5395682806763,-79.,52.056104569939));
#478=LINE('',#477,#476);
#479=EDGE_CURVE('E60',#472,#39,#478,.T.);
#480=ORIENTED_EDGE('',*,*,#479,.T.);
#481=EDGE_LOOP('',(#303,#311,#474,#480));
#482=FACE_BOUND('',#481,.T.);
#483=ADVANCED_FACE('F116',(#482),#302,.T.);
#484=CARTESIAN_POINT('',(-29.5395682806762,-79.,52.056104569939));
#485=DIRECTION('',(-1.,0.,0.));
#486=DIRECTION('',(0.,0.,1.));
#487=AXIS2_PLACEMENT_3D('',#484,#485,#486);
#488=PLANE('',#487);
#489=ORIENTED_EDGE('',*,*,#310,.T.);
#490=ORIENTED_EDGE('',*,*,#32,.T.);
#491=DIRECTION('',(0.,1.,0.));
#492=VECTOR('',#491,1.);
#493=CARTESIAN_POINT('',(-29.5395682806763,-79.,0.));
#494=LINE('',#493,#492);
#495=CARTESIAN_POINT('',(-29.5395682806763,-27.9706118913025,0.));
#496=VERTEX_POINT('',#495);
#497=EDGE_CURVE('E97',#496,#31,#494,.T.);
#498=ORIENTED_EDGE('',*,*,#497,.F.);
#499=DIRECTION('',(0.,0.,-1.));
#500=VECTOR('',#499,1.);
#501=CARTESIAN_POINT('',(-29.5395682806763,-27.9706118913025,-21.4946060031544));
#502=LINE('',#501,#500);
#503=EDGE_CURVE('E101',#309,#496,#502,.T.);
#504=ORIENTED_EDGE('',*,*,#503,.F.);
#505=EDGE_LOOP('',(#489,#490,#498,#504));
#506=FACE_BOUND('',#505,.T.);
#507=ADVANCED_FACE('F144',(#506),#488,.T.);
#508=CARTESIAN_POINT('',(29.5395682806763,-79.,0.));
#509=DIRECTION('',(0.,0.,-1.));
#510=DIRECTION('',(-1.,0.,0.));
#511=AXIS2_PLACEMENT_3D('',#508,#509,#510);
#512=PLANE('',#511);
#513=ORIENTED_EDGE('',*,*,#497,.T.);
#514=ORIENTED_EDGE('',*,*,#54,.T.);
#515=DIRECTION('',(0.,1.,0.));
#516=VECTOR('',#515,1.);
#517=CARTESIAN_POINT('',(29.5395682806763,-79.,0.));
#518=LINE('',#517,#516);
#519=CARTESIAN_POINT('',(29.5395682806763,-27.9706118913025,0.));
#520=VERTEX_POINT('',#519);
#521=EDGE_CURVE('E65',#520,#47,#518,.T.);
#522=ORIENTED_EDGE('',*,*,#521,.F.);
#523=DIRECTION('',(1.,0.,0.));
#524=VECTOR('',#523,1.);
#525=CARTESIAN_POINT('',(39.5,-27.9706118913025,0.));
#526=LINE('',#525,#524);
#527=EDGE_CURVE('E88',#496,#520,#526,.T.);
#528=ORIENTED_EDGE('',*,*,#527,.F.);
#529=EDGE_LOOP('',(#513,#514,#522,#528));
#530=FACE_BOUND('',#529,.T.);
#531=ADVANCED_FACE('F93',(#530),#512,.T.);
#532=CARTESIAN_POINT('',(29.5395682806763,-79.,0.));
#533=DIRECTION('',(1.,0.,0.));
#534=DIRECTION('',(0.,0.,-1.));
#535=AXIS2_PLACEMENT_3D('',#532,#533,#534);
#536=PLANE('',#535);
#537=ORIENTED_EDGE('',*,*,#521,.T.);
#538=ORIENTED_EDGE('',*,*,#48,.T.);
#539=ORIENTED_EDGE('',*,*,#479,.F.);
#540=DIRECTION('',(0.,0.,1.));
#541=VECTOR('',#540,1.);
#542=CARTESIAN_POINT('',(29.5395682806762,-27.9706118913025,-21.4946060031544));
#543=LINE('',#542,#541);
#544=EDGE_CURVE('E82',#520,#472,#543,.T.);
#545=ORIENTED_EDGE('',*,*,#544,.F.);
#546=EDGE_LOOP('',(#537,#538,#539,#545));
#547=FACE_BOUND('',#546,.T.);
#548=ADVANCED_FACE('F83',(#547),#536,.T.);
#549=CARTESIAN_POINT('',(39.5,-78.6919749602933,52.056104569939));
#550=DIRECTION('',(-1.,0.,0.));
#551=DIRECTION('',(0.,0.,1.));
#552=AXIS2_PLACEMENT_3D('',#549,#550,#551);
#553=CYLINDRICAL_SURFACE('',#552,50.7213630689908);
#554=DIRECTION('',(-1.,0.,0.));
#555=VECTOR('',#554,1.);
#556=CARTESIAN_POINT('',(39.5,-27.9706118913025,52.056104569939));
#557=LINE('',#556,#555);
#558=EDGE_CURVE('E128',#472,#309,#557,.T.);
#559=ORIENTED_EDGE('',*,*,#558,.F.);
#560=ORIENTED_EDGE('',*,*,#473,.T.);
#561=EDGE_LOOP('',(#559,#560));
#562=FACE_BOUND('',#561,.T.);
#563=ADVANCED_FACE('F156',(#562),#553,.F.);
#564=CARTESIAN_POINT('',(39.5,-27.9706118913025,-21.4946060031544));
#565=DIRECTION('',(0.,-1.,0.));
#566=DIRECTION('',(0.,0.,-1.));
#567=AXIS2_PLACEMENT_3D('',#564,#565,#566);
#568=PLANE('',#567);
#569=ORIENTED_EDGE('',*,*,#558,.T.);
#570=ORIENTED_EDGE('',*,*,#503,.T.);
#571=ORIENTED_EDGE('',*,*,#527,.T.);
#572=ORIENTED_EDGE('',*,*,#544,.T.);
#573=EDGE_LOOP('',(#569,#570,#571,#572));
#574=FACE_BOUND('',#573,.T.);
#575=ADVANCED_FACE('F100',(#574),#568,.T.);
#576=CLOSED_SHELL('',(#58,#228,#483,#507,#531,#548,#563,#575));
#577=MANIFOLD_SOLID_BREP('B2',#576);
#578=CARTESIAN_POINT('',(0.,0.,150.));
#579=DIRECTION('',(0.,0.,-1.));
#580=DIRECTION('',(-1.,0.,0.));
#581=AXIS2_PLACEMENT_3D('',#578,#579,#580);
#582=CYLINDRICAL_SURFACE('',#581,41.);
#583=DIRECTION('',(0.,0.,-1.));
#584=VECTOR('',#583,1.);
#585=CARTESIAN_POINT('',(-30.8801893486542,-26.9706118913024,150.));
#586=LINE('',#585,#584);
#587=CARTESIAN_POINT('',(-30.8801893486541,-26.9706118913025,52.056104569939));
#588=VERTEX_POINT('',#587);
#589=CARTESIAN_POINT('',(-30.8801893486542,-26.9706118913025,0.));
#590=VERTEX_POINT('',#589);
#591=EDGE_CURVE('E237',#588,#590,#586,.T.);
#592=ORIENTED_EDGE('',*,*,#591,.F.);
#593=CARTESIAN_POINT('',(30.8801893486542,-26.9706118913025,52.056104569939));
#594=CARTESIAN_POINT('',(30.8801759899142,-26.970602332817,52.5729254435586));
#595=CARTESIAN_POINT('',(30.8734231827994,-26.9783582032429,53.0897436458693));
#596=CARTESIAN_POINT('',(30.8463429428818,-27.0093299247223,54.1225684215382));
#597=CARTESIAN_POINT('',(30.8260152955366,-27.0325460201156,54.6385749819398));
#598=CARTESIAN_POINT('',(30.7716821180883,-27.0943758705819,55.6690964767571));
#599=CARTESIAN_POINT('',(30.7376728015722,-27.132993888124,56.183610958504));
#600=CARTESIAN_POINT('',(30.6557912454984,-27.2254697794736,57.2101267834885));
#601=CARTESIAN_POINT('',(30.6079190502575,-27.2793276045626,57.7221281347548));
#602=CARTESIAN_POINT('',(30.4426261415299,-27.4640608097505,59.2579029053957));
#603=CARTESIAN_POINT('',(30.3037676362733,-27.6178165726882,60.2768168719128));
#604=CARTESIAN_POINT('',(29.9662953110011,-27.983617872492,62.2939169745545));
#605=CARTESIAN_POINT('',(29.7676859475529,-28.1956590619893,63.292104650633));
#606=CARTESIAN_POINT('',(29.3063122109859,-28.6749198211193,65.263096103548));
#607=CARTESIAN_POINT('',(29.0433776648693,-28.9422854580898,66.2358248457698));
#608=CARTESIAN_POINT('',(28.4492278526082,-29.5265122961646,68.145019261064));
#609=CARTESIAN_POINT('',(28.1180105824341,-29.8433749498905,69.0814838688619));
#610=CARTESIAN_POINT('',(27.3834951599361,-30.5187229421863,70.9077070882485));
#611=CARTESIAN_POINT('',(26.9803470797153,-30.8771210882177,71.7975580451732));
#612=CARTESIAN_POINT('',(26.0974190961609,-31.6268846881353,73.5237980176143));
#613=CARTESIAN_POINT('',(25.6176479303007,-32.0182463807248,74.3601931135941));
#614=CARTESIAN_POINT('',(24.6146155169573,-32.7947293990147,75.9149468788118));
#615=CARTESIAN_POINT('',(24.0966862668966,-33.1783975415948,76.6374689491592));
#616=CARTESIAN_POINT('',(22.9909504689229,-33.9539677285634,78.022233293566));
#617=CARTESIAN_POINT('',(22.4031462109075,-34.3458695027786,78.6844775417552));
#618=CARTESIAN_POINT('',(21.1588664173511,-35.1260748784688,79.9426549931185));
#619=CARTESIAN_POINT('',(20.5024247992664,-35.5143801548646,80.5386206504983));
#620=CARTESIAN_POINT('',(19.123637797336,-36.2754183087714,81.6600656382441));
#621=CARTESIAN_POINT('',(18.4013016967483,-36.6481533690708,82.1855548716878));
#622=CARTESIAN_POINT('',(16.9971178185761,-37.317814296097,83.0972711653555));
#623=CARTESIAN_POINT('',(16.3228816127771,-37.6181952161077,83.492722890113));
#624=CARTESIAN_POINT('',(14.9332785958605,-38.1911211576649,84.2274790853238));
#625=CARTESIAN_POINT('',(14.2179157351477,-38.4636688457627,84.5667889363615));
#626=CARTESIAN_POINT('',(12.7513183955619,-38.9744381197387,85.1888493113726));
#627=CARTESIAN_POINT('',(12.0000862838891,-39.2126619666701,85.4716035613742));
#628=CARTESIAN_POINT('',(10.4675376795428,-39.6492798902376,85.9807261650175));
#629=CARTESIAN_POINT('',(9.68622160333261,-39.847674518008,86.2070952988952));
#630=CARTESIAN_POINT('',(8.14543337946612,-40.1900306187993,86.5924943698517));
#631=CARTESIAN_POINT('',(7.38728875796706,-40.3364662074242,86.7546480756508));
#632=CARTESIAN_POINT('',(5.85529424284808,-40.5871644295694,87.0297733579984));
#633=CARTESIAN_POINT('',(5.08144509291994,-40.6914290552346,87.142747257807));
#634=CARTESIAN_POINT('',(3.523588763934,-40.8558173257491,87.3199557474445));
#635=CARTESIAN_POINT('',(2.73958206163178,-40.9159430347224,87.3841926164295));
#636=CARTESIAN_POINT('',(1.16693576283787,-40.9909499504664,87.4642269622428));
#637=CARTESIAN_POINT('',(0.378296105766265,-41.0058305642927,87.4800238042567));
#638=CARTESIAN_POINT('',(-1.19776578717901,-40.9900746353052,87.4632541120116));
#639=CARTESIAN_POINT('',(-1.98518832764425,-40.9594523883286,87.4307027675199));
#640=CARTESIAN_POINT('',(-3.55347837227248,-40.8532799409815,87.3171111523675));
#641=CARTESIAN_POINT('',(-4.33434590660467,-40.7777299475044,87.2360711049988));
#642=CARTESIAN_POINT('',(-5.88391605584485,-40.5831151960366,87.0251589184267));
#643=CARTESIAN_POINT('',(-6.65261952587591,-40.4640535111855,86.8952902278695));
#644=CARTESIAN_POINT('',(-8.1724197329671,-40.1846799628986,86.5862503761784));
#645=CARTESIAN_POINT('',(-8.92351652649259,-40.0243682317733,86.4070793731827));
#646=CARTESIAN_POINT('',(-10.4026300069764,-39.6656566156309,85.9989918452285));
#647=CARTESIAN_POINT('',(-11.1306500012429,-39.4672622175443,85.7700824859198));
#648=CARTESIAN_POINT('',(-12.5585787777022,-39.0363710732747,85.2621777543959));
#649=CARTESIAN_POINT('',(-13.2584877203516,-38.8038745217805,84.9831826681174));
#650=CARTESIAN_POINT('',(-14.6252896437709,-38.3096454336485,84.3751425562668));
#651=CARTESIAN_POINT('',(-15.2921888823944,-38.0479184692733,84.0461070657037));
#652=CARTESIAN_POINT('',(-16.588857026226,-37.5007341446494,83.3383843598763));
#653=CARTESIAN_POINT('',(-17.2186260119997,-37.2152768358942,82.9596972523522));
#654=CARTESIAN_POINT('',(-18.4372087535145,-36.6268618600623,82.1538509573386));
#655=CARTESIAN_POINT('',(-19.0260394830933,-36.323911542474,81.72671205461));
#656=CARTESIAN_POINT('',(-20.1602862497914,-35.7068587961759,80.825486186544));
#657=CARTESIAN_POINT('',(-20.7057025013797,-35.3927564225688,80.3513994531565));
#658=CARTESIAN_POINT('',(-21.751318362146,-34.7599440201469,79.3585318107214));
#659=CARTESIAN_POINT('',(-22.2515156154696,-34.4412337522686,78.8397485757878));
#660=CARTESIAN_POINT('',(-23.2057680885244,-33.8056369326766,77.7603515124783));
#661=CARTESIAN_POINT('',(-23.6598218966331,-33.4887504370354,77.1997364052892));
#662=CARTESIAN_POINT('',(-24.5408835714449,-32.8489655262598,76.0142213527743));
#663=CARTESIAN_POINT('',(-24.9657964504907,-32.5264245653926,75.3875725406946));
#664=CARTESIAN_POINT('',(-25.7660773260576,-31.8962188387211,74.096357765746));
#665=CARTESIAN_POINT('',(-26.1414438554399,-31.5885545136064,73.4317906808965));
#666=CARTESIAN_POINT('',(-26.8443350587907,-30.993449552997,72.0686855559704));
#667=CARTESIAN_POINT('',(-27.1718342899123,-30.7060197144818,71.3701297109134));
#668=CARTESIAN_POINT('',(-27.7807348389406,-30.1562440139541,69.9437149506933));
#669=CARTESIAN_POINT('',(-28.0621345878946,-29.8938990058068,69.2158550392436));
#670=CARTESIAN_POINT('',(-28.610935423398,-29.3696216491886,67.6497811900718));
#671=CARTESIAN_POINT('',(-28.8729931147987,-29.1112155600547,66.8085112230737));
#672=CARTESIAN_POINT('',(-29.3456448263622,-28.6346950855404,65.1004373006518));
#673=CARTESIAN_POINT('',(-29.5562315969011,-28.4165863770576,64.2336297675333));
#674=CARTESIAN_POINT('',(-29.9287657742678,-28.0239583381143,62.4800513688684));
#675=CARTESIAN_POINT('',(-30.090718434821,-27.8494342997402,61.5932826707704));
#676=CARTESIAN_POINT('',(-30.3684186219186,-27.5463484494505,59.8050870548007));
#677=CARTESIAN_POINT('',(-30.48417754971,-27.4177752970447,58.903663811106));
#678=CARTESIAN_POINT('',(-30.6793894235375,-27.1992391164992,57.0136494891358));
#679=CARTESIAN_POINT('',(-30.7549252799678,-27.1134811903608,56.0241557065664));
#680=CARTESIAN_POINT('',(-30.8302011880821,-27.0277614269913,54.5369546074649));
#681=CARTESIAN_POINT('',(-30.8489553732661,-27.0063410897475,54.0412798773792));
#682=CARTESIAN_POINT('',(-30.8739449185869,-26.9777637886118,53.0491226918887));
#683=CARTESIAN_POINT('',(-30.8801782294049,-26.9706091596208,52.5526401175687));
#684=CARTESIAN_POINT('',(-30.8801893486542,-26.9706118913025,52.056104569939));
#685=B_SPLINE_CURVE_WITH_KNOTS('',3,(#593,#594,#595,#596,#597,#598,#599,#600,#601,#602,#603,
#604,#605,#606,#607,#608,#609,#610,#611,#612,#613,#614,#615,#616,#617,#618,#619,#620,#621,#622,
#623,#624,#625,#626,#627,#628,#629,#630,#631,#632,#633,#634,#635,#636,#637,#638,#639,#640,#641,
#642,#643,#644,#645,#646,#647,#648,#649,#650,#651,#652,#653,#654,#655,#656,#657,#658,#659,#660,
#661,#662,#663,#664,#665,#666,#667,#668,#669,#670,#671,#672,#673,#674,#675,#676,#677,#678,#679,
#680,#681,#682,#683,#684),.UNSPECIFIED.,.F.,.F.,(4,2,2,2,2,2,2,2,2,2,2,2,2,2,2,2,2,2,2,2,2,2,2,
2,2,2,2,2,2,2,2,2,2,2,2,2,2,2,2,2,2,2,2,2,2,4),(0.,1.55035446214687,3.10073342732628,
4.65154175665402,6.20234512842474,9.31784552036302,12.4331135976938,15.556714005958,
18.6804061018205,21.7976557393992,24.9145501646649,27.8150461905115,30.7154471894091,
33.6144216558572,36.512988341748,39.0218861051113,41.5305432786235,44.0390351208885,
46.5474922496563,48.9117010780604,51.2757982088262,53.6397847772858,56.003802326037,
58.3670773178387,60.730341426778,63.0934386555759,65.4565283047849,67.8192777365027,
70.1820136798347,72.5442999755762,74.9065811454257,77.2678769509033,79.6291610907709,
81.9905681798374,84.3520474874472,86.8183429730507,89.2847114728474,91.7523861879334,
94.2201448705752,96.9720729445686,99.7243884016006,102.476406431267,105.227744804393,
108.212687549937,109.701853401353,111.191262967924),.UNSPECIFIED.);
#686=CARTESIAN_POINT('',(30.8801893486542,-26.9706118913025,52.056104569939));
#687=VERTEX_POINT('',#686);
#688=EDGE_CURVE('E241',#687,#588,#685,.T.);
#689=ORIENTED_EDGE('',*,*,#688,.F.);
#690=DIRECTION('',(0.,0.,-1.));
#691=VECTOR('',#690,1.);
#692=CARTESIAN_POINT('',(30.8801893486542,-26.9706118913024,150.));
#693=LINE('',#692,#691);
#694=CARTESIAN_POINT('',(30.8801893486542,-26.9706118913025,0.));
#695=VERTEX_POINT('',#694);
#696=EDGE_CURVE('E296',#695,#687,#693,.F.);
#697=ORIENTED_EDGE('',*,*,#696,.F.);
#698=CARTESIAN_POINT('',(0.,0.,0.));
#699=DIRECTION('',(0.,0.,1.));
#700=DIRECTION('',(1.,0.,0.));
#701=AXIS2_PLACEMENT_3D('',#698,#699,#700);
#702=CIRCLE('',#701,41.);
#703=CARTESIAN_POINT('',(0.102500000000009,40.9998718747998,0.));
#704=VERTEX_POINT('',#703);
#705=EDGE_CURVE('E285',#695,#704,#702,.T.);
#706=ORIENTED_EDGE('',*,*,#705,.T.);
#707=DIRECTION('',(0.,0.,-1.));
#708=VECTOR('',#707,1.);
#709=CARTESIAN_POINT('',(0.102500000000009,40.9998718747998,150.));
#710=LINE('',#709,#708);
#711=CARTESIAN_POINT('',(0.102500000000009,40.9998718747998,150.));
#712=VERTEX_POINT('',#711);
#713=EDGE_CURVE('E305',#712,#704,#710,.T.);
#714=ORIENTED_EDGE('',*,*,#713,.F.);
#715=CARTESIAN_POINT('',(0.,0.,150.));
#716=DIRECTION('',(0.,0.,1.));
#717=DIRECTION('',(1.,0.,0.));
#718=AXIS2_PLACEMENT_3D('',#715,#716,#717);
#719=CIRCLE('',#718,41.);
#720=CARTESIAN_POINT('',(0.,41.,150.));
#721=VERTEX_POINT('',#720);
#722=EDGE_CURVE('E320',#721,#712,#719,.T.);
#723=ORIENTED_EDGE('',*,*,#722,.F.);
#724=DIRECTION('',(0.,0.,-1.));
#725=VECTOR('',#724,1.);
#726=CARTESIAN_POINT('',(0.,41.,150.));
#727=LINE('',#726,#725);
#728=CARTESIAN_POINT('',(0.,41.,0.));
#729=VERTEX_POINT('',#728);
#730=EDGE_CURVE('E314',#721,#729,#727,.T.);
#731=ORIENTED_EDGE('',*,*,#730,.T.);
#732=EDGE_CURVE('E294',#729,#590,#702,.T.);
#733=ORIENTED_EDGE('',*,*,#732,.T.);
#734=EDGE_LOOP('',(#592,#689,#697,#706,#714,#723,#731,#733));
#735=FACE_BOUND('',#734,.T.);
#736=ADVANCED_FACE('F217',(#735),#582,.T.);
#737=CARTESIAN_POINT('',(0.,0.,150.));
#738=DIRECTION('',(0.,0.,-1.));
#739=DIRECTION('',(-1.,0.,0.));
#740=AXIS2_PLACEMENT_3D('',#737,#738,#739);
#741=CYLINDRICAL_SURFACE('',#740,40.);
#742=CARTESIAN_POINT('',(29.5395682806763,-26.9706118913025,52.056104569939));
#743=CARTESIAN_POINT('',(29.5395552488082,-26.9706025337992,52.5614327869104));
#744=CARTESIAN_POINT('',(29.5328061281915,-26.9780175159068,53.0667584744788));
#745=CARTESIAN_POINT('',(29.5057423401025,-27.0076268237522,54.0766210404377));
#746=CARTESIAN_POINT('',(29.4854274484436,-27.0298213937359,54.5811579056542));
#747=CARTESIAN_POINT('',(29.4311308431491,-27.0889291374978,55.5887889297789));
#748=CARTESIAN_POINT('',(29.3971451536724,-27.125846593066,56.0918826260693));
#749=CARTESIAN_POINT('',(29.315326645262,-27.2142459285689,57.0956250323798));
#750=CARTESIAN_POINT('',(29.2674938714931,-27.265727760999,57.5962737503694));
#751=CARTESIAN_POINT('',(29.1023190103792,-27.4423358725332,59.0983224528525));
#752=CARTESIAN_POINT('',(28.9635550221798,-27.5893395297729,60.0949899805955));
#753=CARTESIAN_POINT('',(28.6263928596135,-27.9390127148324,62.0681142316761));
#754=CARTESIAN_POINT('',(28.4279992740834,-28.1416779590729,63.0445725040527));
#755=CARTESIAN_POINT('',(27.9672510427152,-28.5996274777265,64.972776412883));
#756=CARTESIAN_POINT('',(27.7047219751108,-28.8550549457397,65.924446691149));
#757=CARTESIAN_POINT('',(27.1116894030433,-29.4129555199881,67.7922914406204));
#758=CARTESIAN_POINT('',(26.7811837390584,-29.7154301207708,68.7084647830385));
#759=CARTESIAN_POINT('',(26.0485300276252,-30.3597007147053,70.4949301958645));
#760=CARTESIAN_POINT('',(25.6465345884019,-30.7014124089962,71.3653149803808));
#761=CARTESIAN_POINT('',(24.7664654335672,-31.4156498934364,73.0534409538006));
#762=CARTESIAN_POINT('',(24.2884009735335,-31.7881719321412,73.8711885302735));
#763=CARTESIAN_POINT('',(23.2910913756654,-32.5250782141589,75.3879632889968));
#764=CARTESIAN_POINT('',(22.7773813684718,-32.8880791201,76.0912993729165));
#765=CARTESIAN_POINT('',(21.6813051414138,-33.6207563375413,77.4386309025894));
#766=CARTESIAN_POINT('',(21.0989411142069,-33.9904324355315,78.0826282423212));
#767=CARTESIAN_POINT('',(19.8669341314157,-34.7249011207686,79.305035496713));
#768=CARTESIAN_POINT('',(19.2173296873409,-35.089696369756,79.8834825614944));
#769=CARTESIAN_POINT('',(17.8537077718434,-35.8027445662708,80.9703908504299));
#770=CARTESIAN_POINT('',(17.1397005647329,-36.1510001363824,81.4788631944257));
#771=CARTESIAN_POINT('',(15.7591693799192,-36.7714099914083,82.3548047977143));
#772=CARTESIAN_POINT('',(15.1005003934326,-37.0473186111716,82.7320384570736));
#773=CARTESIAN_POINT('',(13.7441312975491,-37.5716281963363,83.4313741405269));
#774=CARTESIAN_POINT('',(13.0464351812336,-37.8200319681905,83.7534817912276));
#775=CARTESIAN_POINT('',(11.6172662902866,-38.283199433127,84.3418687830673));
#776=CARTESIAN_POINT('',(10.8857974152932,-38.4979669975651,84.6081545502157));
#777=CARTESIAN_POINT('',(9.39480612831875,-38.8887057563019,85.0847928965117));
#778=CARTESIAN_POINT('',(8.63528437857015,-39.0646778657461,85.2951467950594));
#779=CARTESIAN_POINT('',(7.14674242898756,-39.363189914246,85.6477061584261));
#780=CARTESIAN_POINT('',(6.41914774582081,-39.4885445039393,85.79356628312));
#781=CARTESIAN_POINT('',(4.95027846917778,-39.6994353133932,86.0370882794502));
#782=CARTESIAN_POINT('',(4.20900463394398,-39.7849737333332,86.1347528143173));
#783=CARTESIAN_POINT('',(2.71819038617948,-39.9145492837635,86.2821223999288));
#784=CARTESIAN_POINT('',(1.96865080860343,-39.9585905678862,86.3318322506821));
#785=CARTESIAN_POINT('',(0.466630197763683,-40.0043346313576,86.3834564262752));
#786=CARTESIAN_POINT('',(-0.28585086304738,-40.0060370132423,86.3853703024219));
#787=CARTESIAN_POINT('',(-1.78256106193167,-39.9672191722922,86.3415754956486));
#788=CARTESIAN_POINT('',(-2.52680928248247,-39.9270219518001,86.296231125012));
#789=CARTESIAN_POINT('',(-4.00754905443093,-39.8056699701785,86.158349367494));
#790=CARTESIAN_POINT('',(-4.7440406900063,-39.7245156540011,86.0658124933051));
#791=CARTESIAN_POINT('',(-6.20396023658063,-39.5228267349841,85.8333286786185));
#792=CARTESIAN_POINT('',(-6.92738940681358,-39.402295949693,85.6933863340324));
#793=CARTESIAN_POINT('',(-8.35611742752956,-39.1242245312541,85.3658422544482));
#794=CARTESIAN_POINT('',(-9.06141630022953,-38.9666839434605,85.1782405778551));
#795=CARTESIAN_POINT('',(-10.4488136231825,-38.6177921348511,84.7552536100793));
#796=CARTESIAN_POINT('',(-11.1309157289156,-38.4264462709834,84.5198758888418));
#797=CARTESIAN_POINT('',(-12.4673584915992,-38.0138667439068,84.0013794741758));
#798=CARTESIAN_POINT('',(-13.1216993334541,-37.792633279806,83.7182610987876));
#799=CARTESIAN_POINT('',(-14.3982809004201,-37.3249458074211,83.1047271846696));
#800=CARTESIAN_POINT('',(-15.0205258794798,-37.0784951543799,82.7743179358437));
#801=CARTESIAN_POINT('',(-16.2293100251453,-36.5655660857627,82.0670327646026));
#802=CARTESIAN_POINT('',(-16.8158489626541,-36.2990875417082,81.6901565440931));
#803=CARTESIAN_POINT('',(-17.955812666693,-35.7490324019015,80.8873733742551));
#804=CARTESIAN_POINT('',(-18.508852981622,-35.4653128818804,80.4610187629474));
#805=CARTESIAN_POINT('',(-19.5731498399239,-34.8892254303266,79.564329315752));
#806=CARTESIAN_POINT('',(-20.0844062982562,-34.5968574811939,79.0939943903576));
#807=CARTESIAN_POINT('',(-21.0637639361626,-34.0094693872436,78.1118229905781));
#808=CARTESIAN_POINT('',(-21.531860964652,-33.7144489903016,77.5999825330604));
#809=CARTESIAN_POINT('',(-22.4242844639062,-33.1275832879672,76.5378074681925));
#810=CARTESIAN_POINT('',(-22.8486093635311,-32.8357380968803,75.9874714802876));
#811=CARTESIAN_POINT('',(-23.6783770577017,-32.2429870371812,74.8167559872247));
#812=CARTESIAN_POINT('',(-24.0810657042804,-31.9426232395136,74.1941507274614));
#813=CARTESIAN_POINT('',(-24.838366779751,-31.3573698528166,72.9134844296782));
#814=CARTESIAN_POINT('',(-25.192977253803,-31.0724808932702,72.255421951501));
#815=CARTESIAN_POINT('',(-25.855933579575,-30.5230441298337,70.9077186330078));
#816=CARTESIAN_POINT('',(-26.1642510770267,-30.2585088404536,70.2180587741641));
#817=CARTESIAN_POINT('',(-26.736349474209,-29.7542103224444,68.8117821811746));
#818=CARTESIAN_POINT('',(-27.0001289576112,-29.5144478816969,68.0951645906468));
#819=CARTESIAN_POINT('',(-27.5163674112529,-29.0342793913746,66.5458149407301));
#820=CARTESIAN_POINT('',(-27.7630536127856,-28.7977207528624,65.709962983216));
#821=CARTESIAN_POINT('',(-28.2055342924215,-28.3644797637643,64.0147145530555));
#822=CARTESIAN_POINT('',(-28.4013206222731,-28.1678037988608,63.1553143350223));
#823=CARTESIAN_POINT('',(-28.7446462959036,-27.8173591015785,61.4186538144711));
#824=CARTESIAN_POINT('',(-28.8922012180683,-27.6635765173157,60.5413993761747));
#825=CARTESIAN_POINT('',(-29.1413686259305,-27.4009744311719,58.7740391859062));
#826=CARTESIAN_POINT('',(-29.2429946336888,-27.2921416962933,57.8839372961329));
#827=CARTESIAN_POINT('',(-29.3952766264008,-27.1280131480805,56.171122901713));
#828=CARTESIAN_POINT('',(-29.4495210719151,-27.0689631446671,55.3490891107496));
#829=CARTESIAN_POINT('',(-29.5036155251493,-27.0099477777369,54.1144705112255));
#830=CARTESIAN_POINT('',(-29.5171017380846,-26.9952026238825,53.70310388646));
#831=CARTESIAN_POINT('',(-29.5350761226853,-26.9755328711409,52.8798689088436));
#832=CARTESIAN_POINT('',(-29.5395627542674,-26.9706099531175,52.4680004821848));
#833=CARTESIAN_POINT('',(-29.5395682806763,-26.9706118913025,52.056104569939));
#834=B_SPLINE_CURVE_WITH_KNOTS('',3,(#742,#743,#744,#745,#746,#747,#748,#749,#750,#751,#752,
#753,#754,#755,#756,#757,#758,#759,#760,#761,#762,#763,#764,#765,#766,#767,#768,#769,#770,#771,
#772,#773,#774,#775,#776,#777,#778,#779,#780,#781,#782,#783,#784,#785,#786,#787,#788,#789,#790,
#791,#792,#793,#794,#795,#796,#797,#798,#799,#800,#801,#802,#803,#804,#805,#806,#807,#808,#809,
#810,#811,#812,#813,#814,#815,#816,#817,#818,#819,#820,#821,#822,#823,#824,#825,#826,#827,#828,
#829,#830,#831,#832,#833),.UNSPECIFIED.,.F.,.F.,(4,2,2,2,2,2,2,2,2,2,2,2,2,2,2,2,2,2,2,2,2,2,2,
2,2,2,2,2,2,2,2,2,2,2,2,2,2,2,2,2,2,2,2,2,2,4),(0.,1.51587959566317,3.03178424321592,
4.54813007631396,6.06447096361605,9.11166092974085,12.1586164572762,15.2139525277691,
18.2693856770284,21.3183730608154,24.3669897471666,27.1935705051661,30.0200610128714,
32.8449415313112,35.6693726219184,38.089111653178,40.5086035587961,42.9278167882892,
45.346972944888,47.6020395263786,49.8569814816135,52.11169770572,54.3664350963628,
56.6039184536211,58.8413775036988,61.0786196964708,63.3158591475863,65.5527443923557,
67.7896147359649,70.0261878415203,72.2627752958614,74.5214616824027,76.7801526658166,
79.0390606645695,81.2980497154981,83.6955846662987,86.0932170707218,88.4923120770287,
90.8914833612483,93.5978088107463,96.3045672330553,99.0104505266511,101.715536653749,
104.191472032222,105.426839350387,106.662418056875),.UNSPECIFIED.);
#835=CARTESIAN_POINT('',(29.5395682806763,-26.9706118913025,52.056104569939));
#836=VERTEX_POINT('',#835);
#837=CARTESIAN_POINT('',(-29.5395682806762,-26.9706118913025,52.056104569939));
#838=VERTEX_POINT('',#837);
#839=EDGE_CURVE('E42',#836,#838,#834,.T.);
#840=ORIENTED_EDGE('',*,*,#839,.T.);
#841=DIRECTION('',(0.,0.,-1.));
#842=VECTOR('',#841,1.);
#843=CARTESIAN_POINT('',(-29.5395682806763,-26.9706118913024,150.));
#844=LINE('',#843,#842);
#845=CARTESIAN_POINT('',(-29.5395682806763,-26.9706118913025,0.));
#846=VERTEX_POINT('',#845);
#847=EDGE_CURVE('E300',#838,#846,#844,.T.);
#848=ORIENTED_EDGE('',*,*,#847,.T.);
#849=CARTESIAN_POINT('',(0.,0.,0.));
#850=DIRECTION('',(0.,0.,1.));
#851=DIRECTION('',(1.,0.,0.));
#852=AXIS2_PLACEMENT_3D('',#849,#850,#851);
#853=CIRCLE('',#852,40.);
#854=CARTESIAN_POINT('',(0.,40.,0.));
#855=VERTEX_POINT('',#854);
#856=EDGE_CURVE('E321',#855,#846,#853,.T.);
#857=ORIENTED_EDGE('',*,*,#856,.F.);
#858=DIRECTION('',(0.,0.,-1.));
#859=VECTOR('',#858,1.);
#860=CARTESIAN_POINT('',(0.,40.,150.));
#861=LINE('',#860,#859);
#862=CARTESIAN_POINT('',(0.,40.,150.));
#863=VERTEX_POINT('',#862);
#864=EDGE_CURVE('E312',#863,#855,#861,.T.);
#865=ORIENTED_EDGE('',*,*,#864,.F.);
#866=CARTESIAN_POINT('',(0.,0.,150.));
#867=DIRECTION('',(0.,0.,1.));
#868=DIRECTION('',(1.,0.,0.));
#869=AXIS2_PLACEMENT_3D('',#866,#867,#868);
#870=CIRCLE('',#869,40.);
#871=CARTESIAN_POINT('',(0.100000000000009,39.9998749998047,150.));
#872=VERTEX_POINT('',#871);
#873=EDGE_CURVE('E328',#863,#872,#870,.T.);
#874=ORIENTED_EDGE('',*,*,#873,.T.);
#875=DIRECTION('',(0.,0.,-1.));
#876=VECTOR('',#875,1.);
#877=CARTESIAN_POINT('',(0.100000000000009,39.9998749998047,150.));
#878=LINE('',#877,#876);
#879=CARTESIAN_POINT('',(0.100000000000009,39.9998749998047,0.));
#880=VERTEX_POINT('',#879);
#881=EDGE_CURVE('E307',#872,#880,#878,.T.);
#882=ORIENTED_EDGE('',*,*,#881,.T.);
#883=CARTESIAN_POINT('',(29.5395682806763,-26.9706118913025,0.));
#884=VERTEX_POINT('',#883);
#885=EDGE_CURVE('E324',#884,#880,#853,.T.);
#886=ORIENTED_EDGE('',*,*,#885,.F.);
#887=DIRECTION('',(0.,0.,-1.));
#888=VECTOR('',#887,1.);
#889=CARTESIAN_POINT('',(29.5395682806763,-26.9706118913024,150.));
#890=LINE('',#889,#888);
#891=EDGE_CURVE('E301',#884,#836,#890,.F.);
#892=ORIENTED_EDGE('',*,*,#891,.T.);
#893=EDGE_LOOP('',(#840,#848,#857,#865,#874,#882,#886,#892));
#894=FACE_BOUND('',#893,.T.);
#895=ADVANCED_FACE('F358',(#894),#741,.F.);
#896=CARTESIAN_POINT('',(0.,0.,0.));
#897=DIRECTION('',(0.,0.,1.));
#898=DIRECTION('',(1.,0.,0.));
#899=AXIS2_PLACEMENT_3D('',#896,#897,#898);
#900=PLANE('',#899);
#901=DIRECTION('',(1.,0.,0.));
#902=VECTOR('',#901,1.);
#903=CARTESIAN_POINT('',(0.,-26.9706118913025,0.));
#904=LINE('',#903,#902);
#905=EDGE_CURVE('E230',#590,#846,#904,.T.);
#906=ORIENTED_EDGE('',*,*,#905,.F.);
#907=ORIENTED_EDGE('',*,*,#732,.F.);
#908=DIRECTION('',(0.,-1.,0.));
#909=VECTOR('',#908,1.);
#910=CARTESIAN_POINT('',(0.,41.,0.));
#911=LINE('',#910,#909);
#912=EDGE_CURVE('E317',#729,#855,#911,.T.);
#913=ORIENTED_EDGE('',*,*,#912,.T.);
#914=ORIENTED_EDGE('',*,*,#856,.T.);
#915=EDGE_LOOP('',(#906,#907,#913,#914));
#916=FACE_BOUND('',#915,.T.);
#917=ADVANCED_FACE('F355',(#916),#900,.F.);
#918=EDGE_CURVE('E288',#884,#695,#904,.T.);
#919=ORIENTED_EDGE('',*,*,#918,.F.);
#920=ORIENTED_EDGE('',*,*,#885,.T.);
#921=DIRECTION('',(0.00250000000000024,0.999996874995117,0.));
#922=VECTOR('',#921,1.);
#923=CARTESIAN_POINT('',(0.100000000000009,39.9998749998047,0.));
#924=LINE('',#923,#922);
#925=EDGE_CURVE('E291',#880,#704,#924,.T.);
#926=ORIENTED_EDGE('',*,*,#925,.T.);
#927=ORIENTED_EDGE('',*,*,#705,.F.);
#928=EDGE_LOOP('',(#919,#920,#926,#927));
#929=FACE_BOUND('',#928,.T.);
#930=ADVANCED_FACE('F286',(#929),#900,.F.);
#931=CARTESIAN_POINT('',(0.100000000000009,39.9998749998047,150.));
#932=DIRECTION('',(-0.999996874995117,0.00250000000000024,0.));
#933=DIRECTION('',(-0.00250000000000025,-0.999996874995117,0.));
#934=AXIS2_PLACEMENT_3D('',#931,#932,#933);
#935=PLANE('',#934);
#936=ORIENTED_EDGE('',*,*,#925,.F.);
#937=ORIENTED_EDGE('',*,*,#881,.F.);
#938=DIRECTION('',(0.00250000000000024,0.999996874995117,0.));
#939=VECTOR('',#938,1.);
#940=CARTESIAN_POINT('',(0.100000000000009,39.9998749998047,150.));
#941=LINE('',#940,#939);
#942=EDGE_CURVE('E331',#872,#712,#941,.T.);
#943=ORIENTED_EDGE('',*,*,#942,.T.);
#944=ORIENTED_EDGE('',*,*,#713,.T.);
#945=EDGE_LOOP('',(#936,#937,#943,#944));
#946=FACE_BOUND('',#945,.T.);
#947=ADVANCED_FACE('F361',(#946),#935,.T.);
#948=CARTESIAN_POINT('',(0.,41.,150.));
#949=DIRECTION('',(1.,0.,0.));
#950=DIRECTION('',(0.,1.,0.));
#951=AXIS2_PLACEMENT_3D('',#948,#949,#950);
#952=PLANE('',#951);
#953=ORIENTED_EDGE('',*,*,#912,.F.);
#954=ORIENTED_EDGE('',*,*,#730,.F.);
#955=DIRECTION('',(0.,-1.,0.));
#956=VECTOR('',#955,1.);
#957=CARTESIAN_POINT('',(0.,41.,150.));
#958=LINE('',#957,#956);
#959=EDGE_CURVE('E316',#721,#863,#958,.T.);
#960=ORIENTED_EDGE('',*,*,#959,.T.);
#961=ORIENTED_EDGE('',*,*,#864,.T.);
#962=EDGE_LOOP('',(#953,#954,#960,#961));
#963=FACE_BOUND('',#962,.T.);
#964=ADVANCED_FACE('F353',(#963),#952,.T.);
#965=CARTESIAN_POINT('',(0.,0.,150.));
#966=DIRECTION('',(0.,0.,1.));
#967=DIRECTION('',(1.,0.,0.));
#968=AXIS2_PLACEMENT_3D('',#965,#966,#967);
#969=PLANE('',#968);
#970=ORIENTED_EDGE('',*,*,#722,.T.);
#971=ORIENTED_EDGE('',*,*,#942,.F.);
#972=ORIENTED_EDGE('',*,*,#873,.F.);
#973=ORIENTED_EDGE('',*,*,#959,.F.);
#974=EDGE_LOOP('',(#970,#971,#972,#973));
#975=FACE_BOUND('',#974,.T.);
#976=ADVANCED_FACE('F345',(#975),#969,.T.);
#977=CARTESIAN_POINT('',(312.756627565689,-78.6919749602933,52.056104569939));
#978=DIRECTION('',(-1.,0.,0.));
#979=DIRECTION('',(0.,0.,1.));
#980=AXIS2_PLACEMENT_3D('',#977,#978,#979);
#981=CYLINDRICAL_SURFACE('',#980,51.7213630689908);
#982=DIRECTION('',(-1.,0.,0.));
#983=VECTOR('',#982,1.);
#984=CARTESIAN_POINT('',(312.756627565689,-26.9706118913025,52.056104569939));
#985=LINE('',#984,#983);
#986=EDGE_CURVE('E458',#687,#836,#985,.T.);
#987=ORIENTED_EDGE('',*,*,#986,.F.);
#988=ORIENTED_EDGE('',*,*,#688,.T.);
#989=EDGE_CURVE('E455',#838,#588,#985,.T.);
#990=ORIENTED_EDGE('',*,*,#989,.F.);
#991=ORIENTED_EDGE('',*,*,#839,.F.);
#992=EDGE_LOOP('',(#987,#988,#990,#991));
#993=FACE_BOUND('',#992,.T.);
#994=ADVANCED_FACE('F340',(#993),#981,.F.);
#995=CARTESIAN_POINT('',(312.756627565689,-26.9706118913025,-21.4946060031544));
#996=DIRECTION('',(0.,-1.,0.));
#997=DIRECTION('',(0.,0.,-1.));
#998=AXIS2_PLACEMENT_3D('',#995,#996,#997);
#999=PLANE('',#998);
#1000=ORIENTED_EDGE('',*,*,#989,.T.);
#1001=ORIENTED_EDGE('',*,*,#591,.T.);
#1002=ORIENTED_EDGE('',*,*,#905,.T.);
#1003=ORIENTED_EDGE('',*,*,#847,.F.);
#1004=EDGE_LOOP('',(#1000,#1001,#1002,#1003));
#1005=FACE_BOUND('',#1004,.T.);
#1006=ADVANCED_FACE('F344',(#1005),#999,.T.);
#1007=ORIENTED_EDGE('',*,*,#918,.T.);
#1008=ORIENTED_EDGE('',*,*,#696,.T.);
#1009=ORIENTED_EDGE('',*,*,#986,.T.);
#1010=ORIENTED_EDGE('',*,*,#891,.F.);
#1011=EDGE_LOOP('',(#1007,#1008,#1009,#1010));
#1012=FACE_BOUND('',#1011,.T.);
#1013=ADVANCED_FACE('F304',(#1012),#999,.T.);
#1014=CLOSED_SHELL('',(#736,#895,#917,#930,#947,#964,#976,#994,#1006,#1013));
#1015=MANIFOLD_SOLID_BREP('B7',#1014);
#1016=ADVANCED_BREP_SHAPE_REPRESENTATION('',(#18,#577,#1015),#14);
#1017=SHAPE_DEFINITION_REPRESENTATION(#9,#1016);
ENDSEC;
END-ISO-10303-21;
